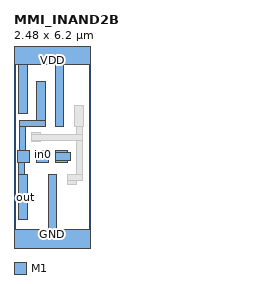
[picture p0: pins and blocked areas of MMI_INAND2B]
MACRO MMI_INAND2B
	CLASS CORE ;
	FOREIGN MMI_INAND2B 0 0 ;
	SIZE 2.48 BY 6.2 ;
	SYMMETRY X Y ;
	SITE CORE1 ;
	PIN out
		DIRECTION output ;
		USE SIGNAL ;
		PORT
			LAYER M1 ;
			RECT 0.75 3.965 1.03 5.24 ;
			LAYER M1 ;
			RECT 0.17 3.775 1.03 3.965 ;
			LAYER M1 ;
			RECT 0.17 2.98 0.365 3.775 ;
			LAYER M1 ;
			RECT 0.75 3.77 1.03 3.775 ;
			LAYER M1 ;
			RECT 0.12 2.6 0.5 2.98 ;
			LAYER M1 ;
			RECT 0.16 2.19 0.355 2.6 ;
			LAYER M1 ;
			RECT 0.16 0.72 0.44 2.19 ;
		END
		AntennaDiffArea 1.2859 ;
	END out
	PIN in1
		DIRECTION input ;
		USE SIGNAL ;
		PORT
			LAYER M1 ;
			RECT 1.36 2.925 1.74 2.98 ;
			LAYER M1 ;
			RECT 1.36 2.645 1.835 2.925 ;
			LAYER M1 ;
			RECT 1.36 2.6 1.74 2.645 ;
		END
		AntennaGateArea 0.17325 ;
	END in1
	PIN GND
		DIRECTION inout ;
		USE GROUND ;
		PORT
			LAYER M1 ;
			RECT 1.12 0.42 1.4 2.19 ;
			LAYER M1 ;
			RECT 0 -0.42 2.48 0.42 ;
		END
	END GND
	PIN VDD
		DIRECTION inout ;
		USE POWER ;
		PORT
			LAYER M1 ;
			RECT 0 5.78 2.48 6.62 ;
			LAYER M1 ;
			RECT 0.16 4.18 0.44 5.78 ;
			LAYER M1 ;
			RECT 1.34 3.77 1.62 5.78 ;
		END
	END VDD
	PIN in0
		DIRECTION input ;
		USE SIGNAL ;
		PORT
			LAYER M1 ;
			RECT 0.88 2.98 1.16 3 ;
			LAYER M1 ;
			RECT 0.74 2.72 1.16 2.98 ;
			LAYER M1 ;
			RECT 0.74 2.6 1.12 2.72 ;
		END
		AntennaGateArea 0.462 ;
	END in0
	OBS
		LAYER M1 ;
		RECT 1.99 3.77 2.27 4.47 ;
		LAYER M1 ;
		RECT 0.57 3.5 0.85 3.57 ;
		LAYER M1 ;
		RECT 2.035 3.5 2.225 3.77 ;
		LAYER M1 ;
		RECT 0.57 3.305 2.225 3.5 ;
		LAYER M1 ;
		RECT 0.57 3.29 0.85 3.305 ;
		LAYER M1 ;
		RECT 2.035 2.195 2.225 3.305 ;
		LAYER M1 ;
		RECT 1.755 2.005 2.225 2.195 ;
		LAYER M1 ;
		RECT 1.755 1.88 2.035 2.005 ;
	END
END MMI_INAND2B
